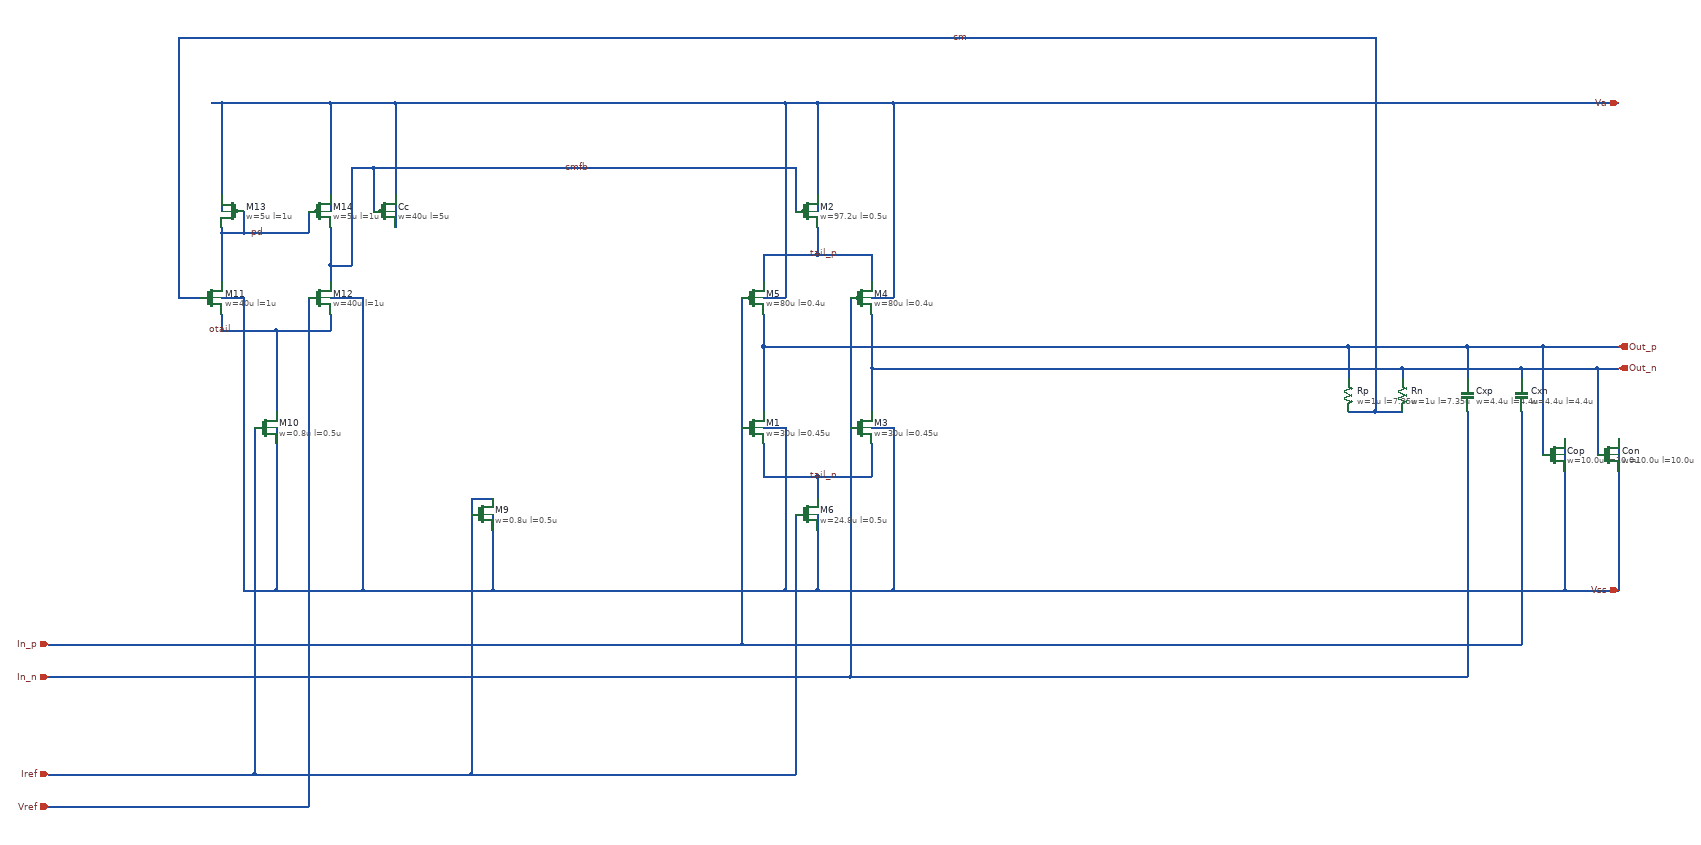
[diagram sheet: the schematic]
v {xschem version=3.4.8RC file_version=1.3}
G {}
K {}
V {}
S {}
F {}
E {}
N 60 -800 1400 -800 {lab=Va}
N 1300 100 1400 100 {lab=Vss}
N -1180 -800 -1180 -600 {lab=Va}
N -980 -800 -980 -600 {lab=Va}
N -860 -800 -860 -570 {lab=Va}
N -80 -800 -80 -600 {lab=Va}
N -180 -440 -140 -440 {lab=Va}
N -140 -800 -140 -440 {lab=Va}
N 20 -440 60 -440 {lab=Va}
N 60 -800 60 -440 {lab=Va}
N -1180 -440 -1140 -440 {lab=Vss}
N -1140 -440 -1140 100 {lab=Vss}
N -980 -440 -920 -440 {lab=Vss}
N -920 -440 -920 100 {lab=Vss}
N -1080 -200 -1080 100 {lab=Vss}
N -680 -40 -680 100 {lab=Vss}
N -80 -40 -80 100 {lab=Vss}
N -180 -200 -140 -200 {lab=Vss}
N -140 -200 -140 100 {lab=Vss}
N 20 -200 60 -200 {lab=Vss}
N 60 -200 60 100 {lab=Vss}
N -80 -520 20 -520 {lab=tail_p}
N -180 -520 -180 -470 {lab=tail_p}
N 20 -520 20 -470 {lab=tail_p}
N -80 -570 -80 -520 {lab=tail_p}
N -80 -110 20 -110 {lab=tail_n}
N -180 -170 -180 -110 {lab=tail_n}
N 20 -170 20 -110 {lab=tail_n}
N -80 -110 -80 -70 {lab=tail_n}
N 1260 -350 1400 -350 {lab=Out_p}
N -180 -410 -180 -350 {lab=Out_p}
N -180 -350 -180 -230 {lab=Out_p}
N 900 -350 900 -290 {lab=Out_p}
N 1120 -350 1120 -290 {lab=Out_p}
N 1360 -310 1400 -310 {lab=Out_n}
N 20 -410 20 -310 {lab=Out_n}
N 20 -310 20 -230 {lab=Out_n}
N 1000 -310 1000 -290 {lab=Out_n}
N 1220 -310 1220 -290 {lab=Out_n}
N 1260 -350 1260 -150 {lab=Out_p}
N 1300 -180 1300 100 {lab=Vss}
N 1360 -310 1360 -150 {lab=Out_n}
N 1400 -180 1400 100 {lab=Vss}
N 950 -230 1000 -230 {lab=cm}
N 950 -920 950 -230 {lab=cm}
N -1260 -920 950 -920 {lab=cm}
N -1260 -920 -1260 -440 {lab=cm}
N -1260 -440 -1220 -440 {lab=cm}
N -980 -500 -980 -470 {lab=cmfb}
N -980 -500 -940 -500 {lab=cmfb}
N -940 -680 -940 -500 {lab=cmfb}
N -900 -680 -120 -680 {lab=cmfb}
N -900 -680 -900 -600 {lab=cmfb}
N -120 -680 -120 -600 {lab=cmfb}
N -1180 -560 -1180 -470 {lab=pd}
N -1140 -560 -1020 -560 {lab=pd}
N -1020 -600 -1020 -560 {lab=pd}
N -1180 -410 -1180 -380 {lab=otail}
N -980 -410 -980 -380 {lab=otail}
N -1080 -380 -980 -380 {lab=otail}
N -1080 -380 -1080 -230 {lab=otail}
N -720 440 -120 440 {lab=Iref}
N -720 -70 -720 440 {lab=Iref}
N -720 -70 -680 -70 {lab=Iref}
N -120 -40 -120 440 {lab=Iref}
N -1120 -200 -1120 440 {lab=Iref}
N -1500 500 -1020 500 {lab=Vref}
N -1020 -440 -1020 500 {lab=Vref}
N -220 200 1220 200 {lab=In_p}
N -220 -440 -220 200 {lab=In_p}
N 1220 -230 1220 200 {lab=In_p}
N -20 260 1120 260 {lab=In_n}
N -20 -440 -20 260 {lab=In_n}
N 1120 -230 1120 260 {lab=In_n}
N -1200 -800 -1180 -800 {lab=Va}
N -1180 -800 -980 -800 {lab=Va}
N -980 -800 -860 -800 {lab=Va}
N -140 -800 -80 -800 {lab=Va}
N -860 -800 -140 -800 {lab=Va}
N -80 -800 60 -800 {lab=Va}
N -1080 100 -920 100 {lab=Vss}
N -1140 100 -1080 100 {lab=Vss}
N -920 100 -680 100 {lab=Vss}
N -140 100 -80 100 {lab=Vss}
N -680 100 -140 100 {lab=Vss}
N -80 100 60 100 {lab=Vss}
N -180 -520 -80 -520 {lab=tail_p}
N -180 -110 -80 -110 {lab=tail_n}
N -180 -350 900 -350 {lab=Out_p}
N 900 -350 1120 -350 {lab=Out_p}
N 20 -310 1000 -310 {lab=Out_n}
N 1000 -310 1220 -310 {lab=Out_n}
N 1120 -350 1260 -350 {lab=Out_p}
N 60 100 1300 100 {lab=Vss}
N 1220 -310 1360 -310 {lab=Out_n}
N 900 -230 950 -230 {lab=cm}
N -980 -570 -980 -500 {lab=cmfb}
N -940 -680 -900 -680 {lab=cmfb}
N -1180 -570 -1180 -560 {lab=pd}
N -1180 -380 -1080 -380 {lab=otail}
N -1120 440 -720 440 {lab=Iref}
N -1500 440 -1120 440 {lab=Iref}
N -1500 200 -220 200 {lab=In_p}
N -1500 260 -20 260 {lab=In_n}
N -1140 -600 -1140 -560 {lab=pd}
N -1180 -560 -1140 -560 {lab=pd}
C {sg13cmos5l_pr/sg13_hv_pmos.sym} -100 -600 0 0 {name=M2
l=0.5u
w=97.2u
 ng=12
 m=1
  mm_ok=1
 model=sg13_hv_pmos
spiceprefix=X
}
C {sg13cmos5l_pr/sg13_hv_pmos.sym} -200 -440 0 0 {name=M5
l=0.4u
w=80u
 ng=40
 m=1
  mm_ok=1
 model=sg13_hv_pmos
spiceprefix=X
}
C {sg13cmos5l_pr/sg13_hv_pmos.sym} 0 -440 0 0 {name=M4
l=0.4u
w=80u
 ng=40
 m=1
  mm_ok=1
 model=sg13_hv_pmos
spiceprefix=X
}
C {sg13cmos5l_pr/sg13_hv_nmos.sym} -200 -200 0 0 {name=M1
l=0.45u
w=30u
 ng=15
 m=1
  mm_ok=1
 model=sg13_hv_nmos
spiceprefix=X
}
C {sg13cmos5l_pr/sg13_hv_nmos.sym} 0 -200 0 0 {name=M3
l=0.45u
w=30u
 ng=15
 m=1
  mm_ok=1
 model=sg13_hv_nmos
spiceprefix=X
}
C {sg13cmos5l_pr/sg13_hv_nmos.sym} -100 -40 0 0 {name=M6
l=0.5u
w=24.8u
 ng=31
 m=4
  mm_ok=1
 model=sg13_hv_nmos
spiceprefix=X
}
C {sg13cmos5l_pr/sg13_hv_nmos.sym} -700 -40 0 0 {name=M9
l=0.5u
w=0.8u
 ng=1
 m=1
  mm_ok=1
 model=sg13_hv_nmos
spiceprefix=X
}
C {sg13cmos5l_pr/sg13_hv_pmos.sym} -1160 -600 0 1 {name=M13
l=1u
w=5u
 ng=1
 m=1
  mm_ok=1
 model=sg13_hv_pmos
spiceprefix=X
}
C {sg13cmos5l_pr/sg13_hv_pmos.sym} -1000 -600 0 0 {name=M14
l=1u
w=5u
 ng=1
 m=1
  mm_ok=1
 model=sg13_hv_pmos
spiceprefix=X
}
C {sg13cmos5l_pr/sg13_hv_nmos.sym} -1200 -440 0 0 {name=M11
l=1u
w=40u
 ng=20
 m=1
  mm_ok=1
 model=sg13_hv_nmos
spiceprefix=X
}
C {sg13cmos5l_pr/sg13_hv_nmos.sym} -1000 -440 0 0 {name=M12
l=1u
w=40u
 ng=20
 m=1
  mm_ok=1
 model=sg13_hv_nmos
spiceprefix=X
}
C {sg13cmos5l_pr/sg13_hv_nmos.sym} -1100 -200 0 0 {name=M10
l=0.5u
w=0.8u
 ng=1
 m=1
  mm_ok=1
 model=sg13_hv_nmos
spiceprefix=X
}
C {sg13cmos5l_pr/sg13_hv_pmos.sym} -880 -600 0 0 {name=Cc
l=5u
w=40u
 ng=8
 m=1
  mm_ok=1
 model=sg13_hv_pmos
spiceprefix=X
}
C {sg13cmos5l_pr/rhigh.sym} 900 -260 0 0 {name=Rp
w=1u
l=7.35u
model=rhigh
body=Vss
spiceprefix=X
b=0
 m=1
  mm_ok=1
}
C {sg13cmos5l_pr/rhigh.sym} 1000 -260 0 0 {name=Rn
w=1u
l=7.35u
model=rhigh
body=Vss
spiceprefix=X
b=0
 m=1
  mm_ok=1
}
C {sg13cmos5l_pr/cap_mfringe.sym} 1120 -260 0 0 {name=Cxp
model=cap_mfringe
w=4.4u
l=4.4u
mmin=1
mmax=4
spiceprefix=X
}
C {sg13cmos5l_pr/cap_mfringe.sym} 1220 -260 0 0 {name=Cxn
model=cap_mfringe
w=4.4u
l=4.4u
mmin=1
mmax=4
spiceprefix=X
}
C {sg13cmos5l_pr/sg13_hv_nmos.sym} 1280 -150 0 0 {name=Cop
l=10.0u
w=10.0u
 ng=1
 m=1
  mm_ok=1
 model=sg13_hv_nmos
spiceprefix=X
}
C {sg13cmos5l_pr/sg13_hv_nmos.sym} 1380 -150 0 0 {name=Con
l=10.0u
w=10.0u
 ng=1
 m=1
  mm_ok=1
 model=sg13_hv_nmos
spiceprefix=X
}
C {lab_pin.sym} -500 -680 0 0 {name=n1 sig_type=std_logic lab=cmfb}
C {lab_pin.sym} 200 -920 0 0 {name=n2 sig_type=std_logic lab=cm}
C {lab_pin.sym} -40 -520 0 0 {name=n3 sig_type=std_logic lab=tail_p}
C {lab_pin.sym} -40 -110 0 0 {name=n5 sig_type=std_logic lab=tail_n}
C {lab_pin.sym} -1100 -560 0 0 {name=n7 sig_type=std_logic lab=pd}
C {lab_pin.sym} -1160 -380 0 0 {name=n8 sig_type=std_logic lab=otail}
C {iopin.sym} 1400 -800 0 0 {name=p1 lab=Va}
C {iopin.sym} 1400 100 0 0 {name=p2 lab=Vss}
C {opin.sym} 1400 -350 0 0 {name=p4 lab=Out_p}
C {opin.sym} 1400 -310 0 0 {name=p5 lab=Out_n}
C {ipin.sym} -1500 200 0 0 {name=p6 lab=In_p}
C {ipin.sym} -1500 260 0 0 {name=p7 lab=In_n}
C {ipin.sym} -1500 440 0 0 {name=p8 lab=Iref}
C {ipin.sym} -1500 500 0 0 {name=p3 lab=Vref}
